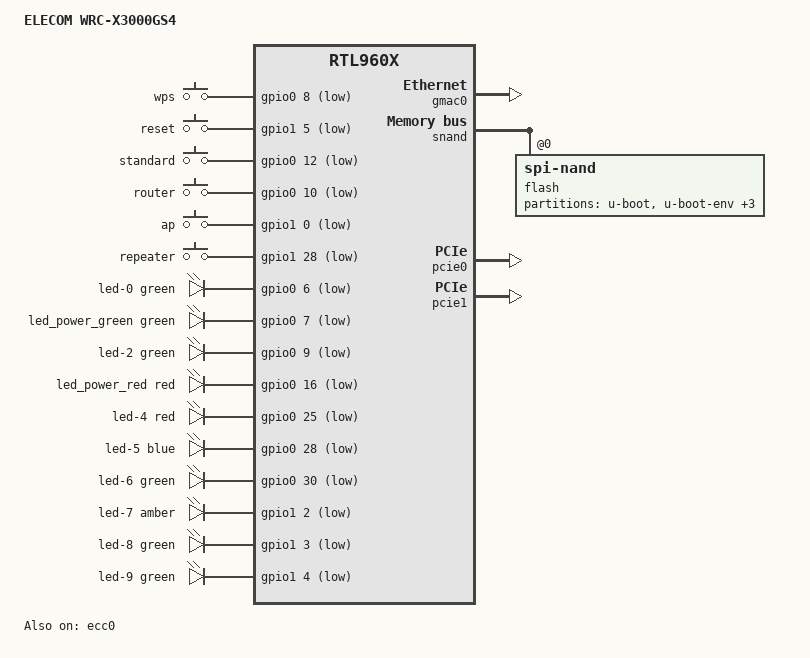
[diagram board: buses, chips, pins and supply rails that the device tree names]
// SPDX-License-Identifier: GPL-2.0-or-later OR MIT

/dts-v1/;

#include <dt-bindings/gpio/gpio.h>
#include <dt-bindings/input/input.h>
#include <dt-bindings/leds/common.h>

#include "rtl9607c-vb.dtsi"

/ {
	compatible = "elecom,wrc-x3000gs4", "realtek,rtl8198d-soc", "realtek,rtl960x-soc";
	model = "ELECOM WRC-X3000GS4";

	chosen {
		bootargs-append = " earlycon";
	};

	aliases {
		led-boot = &led_power_green;
		led-failsafe = &led_power_red;
		led-running = &led_power_green;
		led-upgrade = &led_power_red;
	};

	keys {
		compatible = "gpio-keys";
		pinctrl-names = "default";
		pinctrl-0 = <&pinmux_keys>;

		button-wps {
			label = "wps";
			gpios = <&gpio0 8 GPIO_ACTIVE_LOW>;
			linux,code = <KEY_WPS_BUTTON>;
		};

		button-reset {
			label = "reset";
			gpios = <&gpio1 5 GPIO_ACTIVE_LOW>;
			linux,code = <KEY_RESTART>;
		};

		/* Location: Standard---Annex (no gpio) */
		switch-standard {
			label = "standard";
			gpios = <&gpio0 12 GPIO_ACTIVE_LOW>;
			linux,code = <BTN_0>;
			linux,input-type = <EV_SW>;
		};

		/* Mode: Router---AP---Repeater */
		switch-router {
			label = "router";
			gpios = <&gpio0 10 GPIO_ACTIVE_LOW>;
			linux,code = <BTN_0>;
			linux,input-type = <EV_SW>;
		};

		switch-ap {
			label = "ap";
			gpios = <&gpio1 0 GPIO_ACTIVE_LOW>;
			linux,code = <BTN_0>;
			linux,input-type = <EV_SW>;
		};

		switch-repeater {
			label = "repeater";
			gpios = <&gpio1 28 GPIO_ACTIVE_LOW>;
			linux,code = <BTN_0>;
			linux,input-type = <EV_SW>;
		};
	};

	leds {
		compatible = "gpio-leds";
		pinctrl-names = "default";
		pinctrl-0 = <&pinmux_leds>;

		led-0 {
			color = <LED_COLOR_ID_GREEN>;
			function = LED_FUNCTION_WAN_ONLINE;
			gpios = <&gpio0 6 GPIO_ACTIVE_LOW>;
		};

		led_power_green: led-1 {
			color = <LED_COLOR_ID_GREEN>;
			function = LED_FUNCTION_POWER;
			gpios = <&gpio0 7 GPIO_ACTIVE_LOW>;
		};

		led-2 {
			color = <LED_COLOR_ID_GREEN>;
			function = LED_FUNCTION_LAN;
			function-enumerator = <3>;
			gpios = <&gpio0 9 GPIO_ACTIVE_LOW>;
		};

		led_power_red: led-3 {
			color = <LED_COLOR_ID_RED>;
			function = LED_FUNCTION_POWER;
			gpios = <&gpio0 16 GPIO_ACTIVE_LOW>;
		};

		led-4 {
			color = <LED_COLOR_ID_RED>;
			function = LED_FUNCTION_WPS;
			gpios = <&gpio0 25 GPIO_ACTIVE_LOW>;
		};

		led-5 {
			color = <LED_COLOR_ID_BLUE>;
			function = LED_FUNCTION_POWER;
			gpios = <&gpio0 28 GPIO_ACTIVE_LOW>;
		};

		led-6 {
			color = <LED_COLOR_ID_GREEN>;
			function = LED_FUNCTION_LAN;
			function-enumerator = <1>;
			gpios = <&gpio0 30 GPIO_ACTIVE_LOW>;
		};

		led-7 {
			color = <LED_COLOR_ID_AMBER>;
			function = LED_FUNCTION_POWER;
			gpios = <&gpio1 2 GPIO_ACTIVE_LOW>;
		};

		led-8 {
			color = <LED_COLOR_ID_GREEN>;
			function = LED_FUNCTION_LAN;
			function-enumerator = <2>;
			gpios = <&gpio1 3 GPIO_ACTIVE_LOW>;
		};

		led-9 {
			color = <LED_COLOR_ID_GREEN>;
			function = LED_FUNCTION_WAN;
			gpios = <&gpio1 4 GPIO_ACTIVE_LOW>;
		};
	};
};

&mdio_ctrl {
	PHY_C22(0, 0)
	PHY_C22(1, 1)
	PHY_C22(2, 2)
	PHY_C22(3, 3)
};

&switch0 {
	ethernet-ports {
		port@0 {
			reg = <0>;
			label = "wan";
			phy-mode = "internal";
			phy-handle = <&phy0>;
		};

		SWITCH_PORT(1, 3, internal)
		SWITCH_PORT(2, 2, internal)
		SWITCH_PORT(3, 1, internal)
	};
};

&pinmux {
	pinmux_keys: keys {
		/*
		 * bank 0: 6, 7, 9, 16, 25, 28, 30
		 * bank 1: 2, 3, 4
		 */
		pinctrl-single,bits = <0x0 0x520102c0 0x520102c0>,
				      <0x4 0x1c 0x1c>;
	};

	pinmux_leds: leds {
		/*
		 * bank 0: 8, 10, 12
		 * bank 1: 0, 5, 28
		 */
		pinctrl-single,bits = <0x0 0x1500 0x1500>,
				      <0x4 0x10000021 0x10000021>;
	};
};

&ecc0 {
	status = "okay";
};

&gmac0 {
	status = "okay";
};

&snand {
	status = "okay";

	flash@0 {
		compatible = "spi-nand";
		reg = <0>;

		nand-ecc-engine = <&ecc0>;
		nand-ecc-strength = <6>;
		nand-ecc-step-size = <512>;
		nand-ecc-algo = "bch";
		nand-ecc-placement = "oob";

		partitions {
			compatible = "fixed-partitions";
			#address-cells = <1>;
			#size-cells = <1>;

			partition@0 {
				label = "u-boot";
				reg = <0x0 0xc0000>;
				read-only;
			};

			partition@c0000 {
				compatible = "u-boot,env-redundant-count";
				label = "u-boot-env";
				reg = <0xc0000 0x20000>;
			};

			partition@e0000 {
				compatible = "u-boot,env-redundant-count";
				label = "u-boot-env2";
				reg = <0xe0000 0x20000>;
			};

			partition@100000 {
				label = "static_conf";
				reg = <0x100000 0x20000>;
				read-only;
			};

			partition@120000 {
				label = "ubi";
				reg = <0x120000 0x7c60000>;
			};
		};
	};
};

&pcie0 {
	status = "okay";
};

&pcie1 {
	status = "okay";
};
